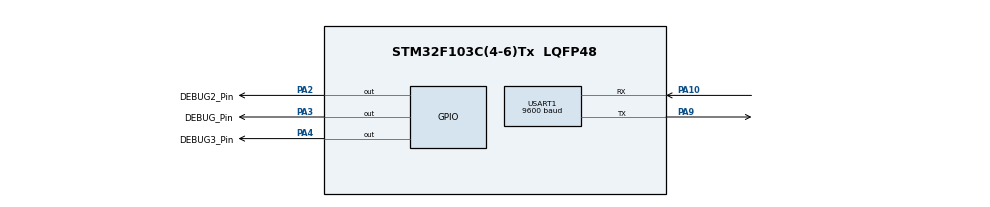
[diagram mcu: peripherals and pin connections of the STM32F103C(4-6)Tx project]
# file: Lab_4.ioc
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Mcu.Family=STM32F1
Mcu.Name=STM32F103C(4-6)Tx
Mcu.Package=LQFP48
NVIC.PriorityGroup=NVIC_PRIORITYGROUP_4
NVIC.TIM2_IRQn=true\:0\:0\:false\:false\:true\:true\:true
NVIC.USART1_IRQn=true\:0\:0\:false\:false\:true\:true\:true
PA10.Mode=Asynchronous
PA10.Signal=USART1_RX
PA2.GPIO_Label=DEBUG2_Pin
PA2.Signal=GPIO_Output
PA3.GPIO_Label=DEBUG_Pin
PA3.Signal=GPIO_Output
PA4.GPIO_Label=DEBUG3_Pin
PA4.Signal=GPIO_Output
PA9.Mode=Asynchronous
PA9.Signal=USART1_TX
ProjectManager.HeapSize=0x200
ProjectManager.StackSize=0x400
ProjectManager.TargetToolchain=STM32CubeIDE
RCC.APB1Freq_Value=8000000
RCC.APB2Freq_Value=8000000
TIM2.Period=99
TIM2.Prescaler=799
USART1.BaudRate=9600
USART1.VirtualMode=VM_ASYNC
VP_SYS_VS_ND.Mode=No_Debug
VP_TIM2_VS_ClockSourceINT.Mode=Internal
board=custom

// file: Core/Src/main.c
/* USER CODE BEGIN Header */
/**
  ******************************************************************************
  * @file           : main.c
  * @brief          : Main program body
  ******************************************************************************
  * @attention
  *
  * <h2><center>&copy; Copyright (c) 2023 STMicroelectronics.
  * All rights reserved.</center></h2>
  *
  * This software component is licensed by ST under BSD 3-Clause license,
  * the "License"; You may not use this file except in compliance with the
  * License. You may obtain a copy of the License at:
  *                        opensource.org/licenses/BSD-3-Clause
  *
  ******************************************************************************
  */
/* USER CODE END Header */
#include "main.h"

TIM_HandleTypeDef htim2;

UART_HandleTypeDef huart1;

void SystemClock_Config(void);
static void MX_GPIO_Init(void);
static void MX_TIM2_Init(void);
static void MX_USART1_UART_Init(void);

int main(void)
{

  /* MCU Configuration--------------------------------------------------------*/

  /* Reset of all peripherals, Initializes the Flash interface and the Systick. */
  HAL_Init();

  /* Configure the system clock */
  SystemClock_Config();

  /* Initialize all configured peripherals */
  MX_GPIO_Init();
  MX_TIM2_Init();
  MX_USART1_UART_Init();

  /* Infinite loop */
  while (1)
  {

  }
}

void SystemClock_Config(void)
{
  RCC_OscInitTypeDef RCC_OscInitStruct = {0};
  RCC_ClkInitTypeDef RCC_ClkInitStruct = {0};

  /** Initializes the RCC Oscillators according to the specified parameters
  * in the RCC_OscInitTypeDef structure.
  */
  RCC_OscInitStruct.OscillatorType = RCC_OSCILLATORTYPE_HSI;
  RCC_OscInitStruct.HSIState = RCC_HSI_ON;
  RCC_OscInitStruct.HSICalibrationValue = RCC_HSICALIBRATION_DEFAULT;
  RCC_OscInitStruct.PLL.PLLState = RCC_PLL_NONE;
  if (HAL_RCC_OscConfig(&RCC_OscInitStruct) != HAL_OK)
  {
    Error_Handler();
  }
  /** Initializes the CPU, AHB and APB buses clocks
  */
  RCC_ClkInitStruct.ClockType = RCC_CLOCKTYPE_HCLK|RCC_CLOCKTYPE_SYSCLK
                              |RCC_CLOCKTYPE_PCLK1|RCC_CLOCKTYPE_PCLK2;
  RCC_ClkInitStruct.SYSCLKSource = RCC_SYSCLKSOURCE_HSI;
  RCC_ClkInitStruct.AHBCLKDivider = RCC_SYSCLK_DIV1;
  RCC_ClkInitStruct.APB1CLKDivider = RCC_HCLK_DIV1;
  RCC_ClkInitStruct.APB2CLKDivider = RCC_HCLK_DIV1;

  if (HAL_RCC_ClockConfig(&RCC_ClkInitStruct, FLASH_LATENCY_0) != HAL_OK)
  {
    Error_Handler();
  }
}

static void MX_TIM2_Init(void)
{

  TIM_ClockConfigTypeDef sClockSourceConfig = {0};
  TIM_MasterConfigTypeDef sMasterConfig = {0};

  htim2.Instance = TIM2;
  htim2.Init.Prescaler = 799;
  htim2.Init.CounterMode = TIM_COUNTERMODE_UP;
  htim2.Init.Period = 99;
  htim2.Init.ClockDivision = TIM_CLOCKDIVISION_DIV1;
  htim2.Init.AutoReloadPreload = TIM_AUTORELOAD_PRELOAD_DISABLE;
  if (HAL_TIM_Base_Init(&htim2) != HAL_OK)
  {
    Error_Handler();
  }
  sClockSourceConfig.ClockSource = TIM_CLOCKSOURCE_INTERNAL;
  if (HAL_TIM_ConfigClockSource(&htim2, &sClockSourceConfig) != HAL_OK)
  {
    Error_Handler();
  }
  sMasterConfig.MasterOutputTrigger = TIM_TRGO_RESET;
  sMasterConfig.MasterSlaveMode = TIM_MASTERSLAVEMODE_DISABLE;
  if (HAL_TIMEx_MasterConfigSynchronization(&htim2, &sMasterConfig) != HAL_OK)
  {
    Error_Handler();
  }

}

static void MX_USART1_UART_Init(void)
{

  huart1.Instance = USART1;
  huart1.Init.BaudRate = 9600;
  huart1.Init.WordLength = UART_WORDLENGTH_8B;
  huart1.Init.StopBits = UART_STOPBITS_1;
  huart1.Init.Parity = UART_PARITY_NONE;
  huart1.Init.Mode = UART_MODE_TX_RX;
  huart1.Init.HwFlowCtl = UART_HWCONTROL_NONE;
  huart1.Init.OverSampling = UART_OVERSAMPLING_16;
  if (HAL_UART_Init(&huart1) != HAL_OK)
  {
    Error_Handler();
  }

}

static void MX_GPIO_Init(void)
{
  GPIO_InitTypeDef GPIO_InitStruct = {0};

  /* GPIO Ports Clock Enable */
  __HAL_RCC_GPIOA_CLK_ENABLE();

  /*Configure GPIO pin Output Level */
  HAL_GPIO_WritePin(GPIOA, DEBUG2_Pin|DEBUG_Pin|DEBUG3_Pin, GPIO_PIN_RESET);

  /*Configure GPIO pins : DEBUG2_Pin DEBUG_Pin DEBUG3_Pin */
  GPIO_InitStruct.Pin = DEBUG2_Pin|DEBUG_Pin|DEBUG3_Pin;
  GPIO_InitStruct.Mode = GPIO_MODE_OUTPUT_PP;
  GPIO_InitStruct.Pull = GPIO_NOPULL;
  GPIO_InitStruct.Speed = GPIO_SPEED_FREQ_LOW;
  HAL_GPIO_Init(GPIOA, &GPIO_InitStruct);

}

void Error_Handler(void)
{
  __disable_irq();
  while (1)
  {
  }
}

/************************ (C) COPYRIGHT STMicroelectronics *****END OF FILE****/
